VERSION 5.7 ;
  NOWIREEXTENSIONATPIN ON ;
  DIVIDERCHAR "/" ;
  BUSBITCHARS "[]" ;
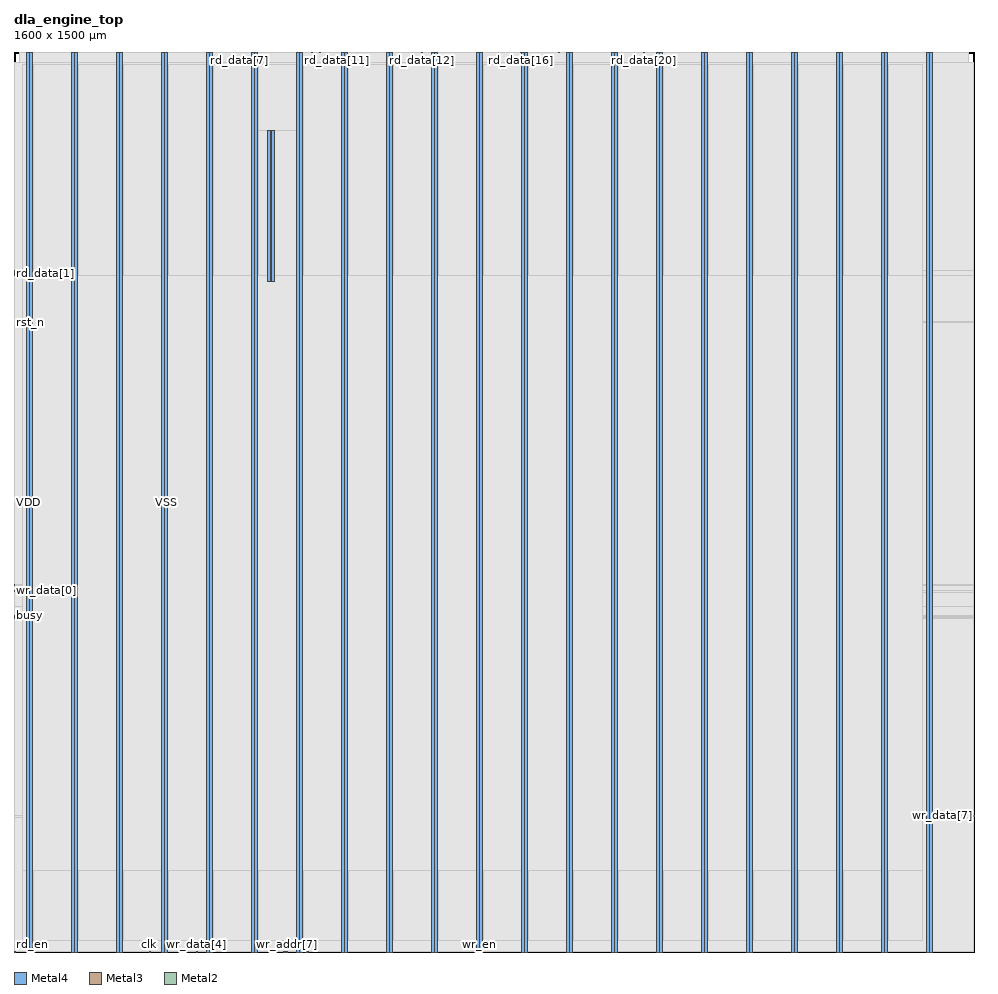
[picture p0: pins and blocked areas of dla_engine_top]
MACRO dla_engine_top
  CLASS BLOCK ;
  FOREIGN dla_engine_top ;
  ORIGIN 0.000 0.000 ;
  SIZE 1600.000 BY 1500.000 ;
  PIN VDD
    DIRECTION INOUT ;
    USE POWER ;
    PORT
      LAYER Metal4 ;
        RECT 20.540 0.000 25.540 1500.000 ;
    END
    PORT
      LAYER Metal4 ;
        RECT 95.540 0.000 100.540 1500.000 ;
    END
    PORT
      LAYER Metal4 ;
        RECT 170.540 0.000 175.540 1500.000 ;
    END
    PORT
      LAYER Metal4 ;
        RECT 245.540 0.000 250.540 1500.000 ;
    END
    PORT
      LAYER Metal4 ;
        RECT 320.540 0.000 325.540 1500.000 ;
    END
    PORT
      LAYER Metal4 ;
        RECT 395.540 0.000 400.540 1500.000 ;
    END
    PORT
      LAYER Metal4 ;
        RECT 470.540 0.000 475.540 1500.000 ;
    END
    PORT
      LAYER Metal4 ;
        RECT 545.540 0.000 550.540 1500.000 ;
    END
    PORT
      LAYER Metal4 ;
        RECT 620.540 0.000 625.540 1500.000 ;
    END
    PORT
      LAYER Metal4 ;
        RECT 695.540 0.000 700.540 1500.000 ;
    END
    PORT
      LAYER Metal4 ;
        RECT 770.540 0.000 775.540 1500.000 ;
    END
    PORT
      LAYER Metal4 ;
        RECT 845.540 0.000 850.540 1500.000 ;
    END
    PORT
      LAYER Metal4 ;
        RECT 920.540 0.000 925.540 1500.000 ;
    END
    PORT
      LAYER Metal4 ;
        RECT 995.540 0.000 1000.540 1500.000 ;
    END
    PORT
      LAYER Metal4 ;
        RECT 1070.540 0.000 1075.540 1500.000 ;
    END
    PORT
      LAYER Metal4 ;
        RECT 1145.540 0.000 1150.540 1500.000 ;
    END
    PORT
      LAYER Metal4 ;
        RECT 1220.540 0.000 1225.540 1500.000 ;
    END
    PORT
      LAYER Metal4 ;
        RECT 1295.540 0.000 1300.540 1500.000 ;
    END
    PORT
      LAYER Metal4 ;
        RECT 1370.540 0.000 1375.540 1500.000 ;
    END
    PORT
      LAYER Metal4 ;
        RECT 1445.540 0.000 1450.540 1500.000 ;
    END
    PORT
      LAYER Metal4 ;
        RECT 1520.540 0.000 1525.540 1500.000 ;
    END
    PORT
      LAYER Metal4 ;
    END
    PORT
      LAYER Metal4 ;
    END
    PORT
      LAYER Metal4 ;
        RECT 422.820 1116.900 427.820 1368.380 ;
    END
  END VDD
  PIN VSS
    DIRECTION INOUT ;
    USE GROUND ;
    PORT
      LAYER Metal4 ;
        RECT 26.540 0.000 31.540 1500.000 ;
    END
    PORT
      LAYER Metal4 ;
        RECT 101.540 0.000 106.540 1500.000 ;
    END
    PORT
      LAYER Metal4 ;
        RECT 176.540 0.000 181.540 1500.000 ;
    END
    PORT
      LAYER Metal4 ;
        RECT 251.540 0.000 256.540 1500.000 ;
    END
    PORT
      LAYER Metal4 ;
        RECT 326.540 0.000 331.540 1500.000 ;
    END
    PORT
      LAYER Metal4 ;
        RECT 401.540 0.000 406.540 1500.000 ;
    END
    PORT
      LAYER Metal4 ;
        RECT 476.540 0.000 481.540 1500.000 ;
    END
    PORT
      LAYER Metal4 ;
        RECT 551.540 0.000 556.540 1500.000 ;
    END
    PORT
      LAYER Metal4 ;
        RECT 626.540 0.000 631.540 1500.000 ;
    END
    PORT
      LAYER Metal4 ;
        RECT 701.540 0.000 706.540 1500.000 ;
    END
    PORT
      LAYER Metal4 ;
        RECT 776.540 0.000 781.540 1500.000 ;
    END
    PORT
      LAYER Metal4 ;
        RECT 851.540 0.000 856.540 1500.000 ;
    END
    PORT
      LAYER Metal4 ;
        RECT 926.540 0.000 931.540 1500.000 ;
    END
    PORT
      LAYER Metal4 ;
        RECT 1001.540 0.000 1006.540 1500.000 ;
    END
    PORT
      LAYER Metal4 ;
        RECT 1076.540 0.000 1081.540 1500.000 ;
    END
    PORT
      LAYER Metal4 ;
        RECT 1151.540 0.000 1156.540 1500.000 ;
    END
    PORT
      LAYER Metal4 ;
        RECT 1226.540 0.000 1231.540 1500.000 ;
    END
    PORT
      LAYER Metal4 ;
        RECT 1301.540 0.000 1306.540 1500.000 ;
    END
    PORT
      LAYER Metal4 ;
        RECT 1376.540 0.000 1381.540 1500.000 ;
    END
    PORT
      LAYER Metal4 ;
        RECT 1451.540 0.000 1456.540 1500.000 ;
    END
    PORT
      LAYER Metal4 ;
        RECT 1526.540 0.000 1531.540 1500.000 ;
    END
    PORT
      LAYER Metal4 ;
    END
    PORT
      LAYER Metal4 ;
    END
    PORT
      LAYER Metal4 ;
        RECT 428.980 1116.900 433.980 1368.380 ;
    END
  END VSS
  PIN busy
    DIRECTION OUTPUT ;
    USE SIGNAL ;
    ANTENNADIFFAREA 1.237600 ;
    PORT
      LAYER Metal3 ;
        RECT 0.000 560.000 0.560 560.560 ;
    END
  END busy
  PIN clk
    DIRECTION INPUT ;
    USE SIGNAL ;
    ANTENNAGATEAREA 4.704000 ;
    ANTENNADIFFAREA 0.877000 ;
    PORT
      LAYER Metal2 ;
        RECT 225.120 0.000 225.680 0.560 ;
    END
  END clk
  PIN done
    DIRECTION OUTPUT ;
    USE SIGNAL ;
    ANTENNADIFFAREA 1.237600 ;
    PORT
      LAYER Metal3 ;
        RECT 0.000 575.680 0.560 576.240 ;
    END
  END done
  PIN rd_addr[0]
    DIRECTION INPUT ;
    USE SIGNAL ;
    ANTENNAGATEAREA 0.666400 ;
    ANTENNADIFFAREA 0.438500 ;
    PORT
      LAYER Metal2 ;
        RECT 495.040 1499.440 495.600 1500.000 ;
    END
  END rd_addr[0]
  PIN rd_addr[1]
    DIRECTION INPUT ;
    USE SIGNAL ;
    ANTENNAGATEAREA 0.666400 ;
    ANTENNADIFFAREA 0.438500 ;
    PORT
      LAYER Metal2 ;
        RECT 498.400 1499.440 498.960 1500.000 ;
    END
  END rd_addr[1]
  PIN rd_addr[2]
    DIRECTION INPUT ;
    USE SIGNAL ;
    ANTENNAGATEAREA 0.666400 ;
    ANTENNADIFFAREA 0.438500 ;
    PORT
      LAYER Metal2 ;
        RECT 493.920 1499.440 494.480 1500.000 ;
    END
  END rd_addr[2]
  PIN rd_addr[3]
    DIRECTION INPUT ;
    USE SIGNAL ;
    ANTENNAGATEAREA 0.666400 ;
    ANTENNADIFFAREA 0.438500 ;
    PORT
      LAYER Metal2 ;
        RECT 496.160 1499.440 496.720 1500.000 ;
    END
  END rd_addr[3]
  PIN rd_data[0]
    DIRECTION OUTPUT ;
    USE SIGNAL ;
    ANTENNADIFFAREA 1.237600 ;
    PORT
      LAYER Metal3 ;
        RECT 0.000 1127.840 0.560 1128.400 ;
    END
  END rd_data[0]
  PIN rd_data[10]
    DIRECTION OUTPUT ;
    USE SIGNAL ;
    ANTENNADIFFAREA 1.237600 ;
    PORT
      LAYER Metal2 ;
        RECT 509.600 1499.440 510.160 1500.000 ;
    END
  END rd_data[10]
  PIN rd_data[11]
    DIRECTION OUTPUT ;
    USE SIGNAL ;
    ANTENNADIFFAREA 1.237600 ;
    PORT
      LAYER Metal2 ;
        RECT 537.600 1499.440 538.160 1500.000 ;
    END
  END rd_data[11]
  PIN rd_data[12]
    DIRECTION OUTPUT ;
    USE SIGNAL ;
    ANTENNADIFFAREA 1.237600 ;
    PORT
      LAYER Metal2 ;
        RECT 679.840 1499.440 680.400 1500.000 ;
    END
  END rd_data[12]
  PIN rd_data[13]
    DIRECTION OUTPUT ;
    USE SIGNAL ;
    ANTENNADIFFAREA 1.237600 ;
    PORT
      LAYER Metal2 ;
        RECT 706.720 1499.440 707.280 1500.000 ;
    END
  END rd_data[13]
  PIN rd_data[14]
    DIRECTION OUTPUT ;
    USE SIGNAL ;
    ANTENNADIFFAREA 1.237600 ;
    PORT
      LAYER Metal2 ;
        RECT 716.800 1499.440 717.360 1500.000 ;
    END
  END rd_data[14]
  PIN rd_data[15]
    DIRECTION OUTPUT ;
    USE SIGNAL ;
    ANTENNADIFFAREA 1.237600 ;
    PORT
      LAYER Metal2 ;
        RECT 745.920 1499.440 746.480 1500.000 ;
    END
  END rd_data[15]
  PIN rd_data[16]
    DIRECTION OUTPUT ;
    USE SIGNAL ;
    ANTENNADIFFAREA 1.237600 ;
    PORT
      LAYER Metal2 ;
        RECT 844.480 1499.440 845.040 1500.000 ;
    END
  END rd_data[16]
  PIN rd_data[17]
    DIRECTION OUTPUT ;
    USE SIGNAL ;
    ANTENNADIFFAREA 1.237600 ;
    PORT
      LAYER Metal2 ;
        RECT 870.240 1499.440 870.800 1500.000 ;
    END
  END rd_data[17]
  PIN rd_data[18]
    DIRECTION OUTPUT ;
    USE SIGNAL ;
    ANTENNADIFFAREA 1.237600 ;
    PORT
      LAYER Metal2 ;
        RECT 879.200 1499.440 879.760 1500.000 ;
    END
  END rd_data[18]
  PIN rd_data[19]
    DIRECTION OUTPUT ;
    USE SIGNAL ;
    ANTENNADIFFAREA 1.237600 ;
    PORT
      LAYER Metal2 ;
        RECT 908.320 1499.440 908.880 1500.000 ;
    END
  END rd_data[19]
  PIN rd_data[1]
    DIRECTION OUTPUT ;
    USE SIGNAL ;
    ANTENNADIFFAREA 1.237600 ;
    PORT
      LAYER Metal3 ;
        RECT 0.000 1131.200 0.560 1131.760 ;
    END
  END rd_data[1]
  PIN rd_data[20]
    DIRECTION OUTPUT ;
    USE SIGNAL ;
    ANTENNADIFFAREA 1.237600 ;
    PORT
      LAYER Metal2 ;
        RECT 1049.440 1499.440 1050.000 1500.000 ;
    END
  END rd_data[20]
  PIN rd_data[21]
    DIRECTION OUTPUT ;
    USE SIGNAL ;
    ANTENNADIFFAREA 1.237600 ;
    PORT
      LAYER Metal2 ;
        RECT 1077.440 1499.440 1078.000 1500.000 ;
    END
  END rd_data[21]
  PIN rd_data[22]
    DIRECTION OUTPUT ;
    USE SIGNAL ;
    ANTENNADIFFAREA 1.237600 ;
    PORT
      LAYER Metal2 ;
        RECT 1087.520 1499.440 1088.080 1500.000 ;
    END
  END rd_data[22]
  PIN rd_data[23]
    DIRECTION OUTPUT ;
    USE SIGNAL ;
    ANTENNADIFFAREA 1.237600 ;
    PORT
      LAYER Metal2 ;
        RECT 1115.520 1499.440 1116.080 1500.000 ;
    END
  END rd_data[23]
  PIN rd_data[2]
    DIRECTION OUTPUT ;
    USE SIGNAL ;
    ANTENNADIFFAREA 1.237600 ;
    PORT
      LAYER Metal3 ;
        RECT 0.000 1132.320 0.560 1132.880 ;
    END
  END rd_data[2]
  PIN rd_data[3]
    DIRECTION OUTPUT ;
    USE SIGNAL ;
    ANTENNADIFFAREA 1.237600 ;
    PORT
      LAYER Metal3 ;
        RECT 0.000 1133.440 0.560 1134.000 ;
    END
  END rd_data[3]
  PIN rd_data[4]
    DIRECTION OUTPUT ;
    USE SIGNAL ;
    ANTENNADIFFAREA 1.237600 ;
    PORT
      LAYER Metal3 ;
        RECT 0.000 1128.960 0.560 1129.520 ;
    END
  END rd_data[4]
  PIN rd_data[5]
    DIRECTION OUTPUT ;
    USE SIGNAL ;
    ANTENNADIFFAREA 1.237600 ;
    PORT
      LAYER Metal3 ;
        RECT 0.000 1130.080 0.560 1130.640 ;
    END
  END rd_data[5]
  PIN rd_data[6]
    DIRECTION OUTPUT ;
    USE SIGNAL ;
    ANTENNADIFFAREA 1.237600 ;
    PORT
      LAYER Metal3 ;
        RECT 0.000 1134.560 0.560 1135.120 ;
    END
  END rd_data[6]
  PIN rd_data[7]
    DIRECTION OUTPUT ;
    USE SIGNAL ;
    ANTENNADIFFAREA 1.237600 ;
    PORT
      LAYER Metal2 ;
        RECT 375.200 1499.440 375.760 1500.000 ;
    END
  END rd_data[7]
  PIN rd_data[8]
    DIRECTION OUTPUT ;
    USE SIGNAL ;
    ANTENNADIFFAREA 1.237600 ;
    PORT
      LAYER Metal2 ;
        RECT 473.760 1499.440 474.320 1500.000 ;
    END
  END rd_data[8]
  PIN rd_data[9]
    DIRECTION OUTPUT ;
    USE SIGNAL ;
    ANTENNADIFFAREA 1.237600 ;
    PORT
      LAYER Metal2 ;
        RECT 500.640 1499.440 501.200 1500.000 ;
    END
  END rd_data[9]
  PIN rd_en
    DIRECTION INPUT ;
    USE SIGNAL ;
    PORT
      LAYER Metal2 ;
        RECT 1.120 0.000 1.680 0.560 ;
    END
  END rd_en
  PIN rst_n
    DIRECTION INPUT ;
    USE SIGNAL ;
    ANTENNAGATEAREA 0.666400 ;
    ANTENNADIFFAREA 0.438500 ;
    PORT
      LAYER Metal3 ;
        RECT 0.000 1049.440 0.560 1050.000 ;
    END
  END rst_n
  PIN start
    DIRECTION INPUT ;
    USE SIGNAL ;
    ANTENNAGATEAREA 0.666400 ;
    ANTENNADIFFAREA 0.438500 ;
    PORT
      LAYER Metal3 ;
        RECT 0.000 556.640 0.560 557.200 ;
    END
  END start
  PIN wb_done
    DIRECTION OUTPUT ;
    USE SIGNAL ;
    ANTENNADIFFAREA 1.237600 ;
    PORT
      LAYER Metal3 ;
        RECT 0.000 611.520 0.560 612.080 ;
    END
  END wb_done
  PIN wr_addr[0]
    DIRECTION INPUT ;
    USE SIGNAL ;
    ANTENNAGATEAREA 0.666400 ;
    ANTENNADIFFAREA 0.438500 ;
    PORT
      LAYER Metal2 ;
        RECT 486.080 0.000 486.640 0.560 ;
    END
  END wr_addr[0]
  PIN wr_addr[1]
    DIRECTION INPUT ;
    USE SIGNAL ;
    ANTENNAGATEAREA 0.666400 ;
    ANTENNADIFFAREA 0.438500 ;
    PORT
      LAYER Metal2 ;
        RECT 480.480 0.000 481.040 0.560 ;
    END
  END wr_addr[1]
  PIN wr_addr[2]
    DIRECTION INPUT ;
    USE SIGNAL ;
    ANTENNAGATEAREA 0.666400 ;
    ANTENNADIFFAREA 0.438500 ;
    PORT
      LAYER Metal2 ;
        RECT 449.120 0.000 449.680 0.560 ;
    END
  END wr_addr[2]
  PIN wr_addr[3]
    DIRECTION INPUT ;
    USE SIGNAL ;
    ANTENNAGATEAREA 0.666400 ;
    ANTENNADIFFAREA 0.438500 ;
    PORT
      LAYER Metal2 ;
        RECT 450.240 0.000 450.800 0.560 ;
    END
  END wr_addr[3]
  PIN wr_addr[4]
    DIRECTION INPUT ;
    USE SIGNAL ;
    ANTENNAGATEAREA 0.666400 ;
    ANTENNADIFFAREA 0.438500 ;
    PORT
      LAYER Metal2 ;
        RECT 451.360 0.000 451.920 0.560 ;
    END
  END wr_addr[4]
  PIN wr_addr[5]
    DIRECTION INPUT ;
    USE SIGNAL ;
    ANTENNAGATEAREA 0.666400 ;
    ANTENNADIFFAREA 0.438500 ;
    PORT
      LAYER Metal2 ;
        RECT 452.480 0.000 453.040 0.560 ;
    END
  END wr_addr[5]
  PIN wr_addr[6]
    DIRECTION INPUT ;
    USE SIGNAL ;
    ANTENNAGATEAREA 0.666400 ;
    ANTENNADIFFAREA 0.438500 ;
    PORT
      LAYER Metal2 ;
        RECT 453.600 0.000 454.160 0.560 ;
    END
  END wr_addr[6]
  PIN wr_addr[7]
    DIRECTION INPUT ;
    USE SIGNAL ;
    ANTENNAGATEAREA 0.666400 ;
    ANTENNADIFFAREA 0.438500 ;
    PORT
      LAYER Metal2 ;
        RECT 454.720 0.000 455.280 0.560 ;
    END
  END wr_addr[7]
  PIN wr_addr[8]
    DIRECTION INPUT ;
    USE SIGNAL ;
    ANTENNAGATEAREA 0.666400 ;
    ANTENNADIFFAREA 0.438500 ;
    PORT
      LAYER Metal2 ;
        RECT 489.440 0.000 490.000 0.560 ;
    END
  END wr_addr[8]
  PIN wr_addr[9]
    DIRECTION INPUT ;
    USE SIGNAL ;
    ANTENNAGATEAREA 0.666400 ;
    ANTENNADIFFAREA 0.438500 ;
    PORT
      LAYER Metal2 ;
        RECT 488.320 0.000 488.880 0.560 ;
    END
  END wr_addr[9]
  PIN wr_data[0]
    DIRECTION INPUT ;
    USE SIGNAL ;
    ANTENNAGATEAREA 0.666400 ;
    ANTENNADIFFAREA 0.438500 ;
    PORT
      LAYER Metal3 ;
        RECT 0.000 601.440 0.560 602.000 ;
    END
  END wr_data[0]
  PIN wr_data[1]
    DIRECTION INPUT ;
    USE SIGNAL ;
    ANTENNAGATEAREA 0.666400 ;
    ANTENNADIFFAREA 0.438500 ;
    PORT
      LAYER Metal3 ;
        RECT 0.000 600.320 0.560 600.880 ;
    END
  END wr_data[1]
  PIN wr_data[2]
    DIRECTION INPUT ;
    USE SIGNAL ;
    ANTENNAGATEAREA 0.666400 ;
    ANTENNADIFFAREA 0.438500 ;
    PORT
      LAYER Metal3 ;
        RECT 0.000 599.200 0.560 599.760 ;
    END
  END wr_data[2]
  PIN wr_data[3]
    DIRECTION INPUT ;
    USE SIGNAL ;
    ANTENNAGATEAREA 0.666400 ;
    ANTENNADIFFAREA 0.438500 ;
    PORT
      LAYER Metal2 ;
        RECT 226.240 0.000 226.800 0.560 ;
    END
  END wr_data[3]
  PIN wr_data[4]
    DIRECTION INPUT ;
    USE SIGNAL ;
    ANTENNAGATEAREA 0.666400 ;
    ANTENNADIFFAREA 0.438500 ;
    PORT
      LAYER Metal2 ;
        RECT 304.640 0.000 305.200 0.560 ;
    END
  END wr_data[4]
  PIN wr_data[5]
    DIRECTION INPUT ;
    USE SIGNAL ;
    ANTENNAGATEAREA 0.666400 ;
    ANTENNADIFFAREA 0.438500 ;
    PORT
      LAYER Metal3 ;
        RECT 1599.440 225.120 1600.000 225.680 ;
    END
  END wr_data[5]
  PIN wr_data[6]
    DIRECTION INPUT ;
    USE SIGNAL ;
    ANTENNAGATEAREA 0.666400 ;
    ANTENNADIFFAREA 0.438500 ;
    PORT
      LAYER Metal3 ;
        RECT 1599.440 226.240 1600.000 226.800 ;
    END
  END wr_data[6]
  PIN wr_data[7]
    DIRECTION INPUT ;
    USE SIGNAL ;
    ANTENNAGATEAREA 0.666400 ;
    ANTENNADIFFAREA 0.438500 ;
    PORT
      LAYER Metal3 ;
        RECT 1599.440 227.360 1600.000 227.920 ;
    END
  END wr_data[7]
  PIN wr_en
    DIRECTION INPUT ;
    USE SIGNAL ;
    ANTENNAGATEAREA 0.666400 ;
    ANTENNADIFFAREA 0.438500 ;
    PORT
      LAYER Metal2 ;
        RECT 776.160 0.000 776.720 0.560 ;
    END
  END wr_en
  PIN wr_sel
    DIRECTION INPUT ;
    USE SIGNAL ;
    ANTENNAGATEAREA 0.666400 ;
    ANTENNADIFFAREA 0.438500 ;
    PORT
      LAYER Metal2 ;
        RECT 778.400 0.000 778.960 0.560 ;
    END
  END wr_sel
  OBS
      LAYER Nwell ;
        RECT 6.290 15.250 1593.630 1482.190 ;
      LAYER Metal1 ;
        RECT 6.720 15.380 1593.200 1482.060 ;
      LAYER Metal2 ;
        RECT 8.820 1499.140 374.900 1499.860 ;
        RECT 376.060 1499.140 473.460 1499.860 ;
        RECT 474.620 1499.140 493.620 1499.860 ;
        RECT 497.020 1499.140 498.100 1499.860 ;
        RECT 499.260 1499.140 500.340 1499.860 ;
        RECT 501.500 1499.140 509.300 1499.860 ;
        RECT 510.460 1499.140 537.300 1499.860 ;
        RECT 538.460 1499.140 679.540 1499.860 ;
        RECT 680.700 1499.140 706.420 1499.860 ;
        RECT 707.580 1499.140 716.500 1499.860 ;
        RECT 717.660 1499.140 745.620 1499.860 ;
        RECT 746.780 1499.140 844.180 1499.860 ;
        RECT 845.340 1499.140 869.940 1499.860 ;
        RECT 871.100 1499.140 878.900 1499.860 ;
        RECT 880.060 1499.140 908.020 1499.860 ;
        RECT 909.180 1499.140 1049.140 1499.860 ;
        RECT 1050.300 1499.140 1077.140 1499.860 ;
        RECT 1078.300 1499.140 1087.220 1499.860 ;
        RECT 1088.380 1499.140 1115.220 1499.860 ;
        RECT 1116.380 1499.140 1591.100 1499.860 ;
        RECT 8.820 0.860 1591.100 1499.140 ;
        RECT 8.820 0.090 224.820 0.860 ;
        RECT 227.100 0.090 304.340 0.860 ;
        RECT 305.500 0.090 448.820 0.860 ;
        RECT 455.580 0.090 480.180 0.860 ;
        RECT 481.340 0.090 485.780 0.860 ;
        RECT 486.940 0.090 488.020 0.860 ;
        RECT 490.300 0.090 775.860 0.860 ;
        RECT 777.020 0.090 778.100 0.860 ;
        RECT 779.260 0.090 1591.100 0.860 ;
      LAYER Metal3 ;
        RECT 0.560 1135.420 1599.440 1482.740 ;
        RECT 0.860 1127.540 1599.440 1135.420 ;
        RECT 0.560 1050.300 1599.440 1127.540 ;
        RECT 0.860 1049.140 1599.440 1050.300 ;
        RECT 0.560 612.380 1599.440 1049.140 ;
        RECT 0.860 611.220 1599.440 612.380 ;
        RECT 0.560 602.300 1599.440 611.220 ;
        RECT 0.860 598.900 1599.440 602.300 ;
        RECT 0.560 576.540 1599.440 598.900 ;
        RECT 0.860 575.380 1599.440 576.540 ;
        RECT 0.560 560.860 1599.440 575.380 ;
        RECT 0.860 559.700 1599.440 560.860 ;
        RECT 0.560 557.500 1599.440 559.700 ;
        RECT 0.860 556.340 1599.440 557.500 ;
        RECT 0.560 228.220 1599.440 556.340 ;
        RECT 0.560 224.820 1599.140 228.220 ;
        RECT 0.560 0.140 1599.440 224.820 ;
      LAYER Metal4 ;
        RECT 422.820 136.900 427.820 388.380 ;
        RECT 422.820 622.980 427.820 882.300 ;
        RECT 428.980 136.900 433.980 388.380 ;
        RECT 428.980 622.980 433.980 882.300 ;
        RECT 13.580 18.570 20.240 1479.430 ;
        RECT 25.840 18.570 26.240 1479.430 ;
        RECT 31.840 18.570 95.240 1479.430 ;
        RECT 100.840 18.570 101.240 1479.430 ;
        RECT 106.840 18.570 170.240 1479.430 ;
        RECT 175.840 18.570 176.240 1479.430 ;
        RECT 181.840 18.570 245.240 1479.430 ;
        RECT 250.840 18.570 251.240 1479.430 ;
        RECT 256.840 18.570 320.240 1479.430 ;
        RECT 325.840 18.570 326.240 1479.430 ;
        RECT 331.840 18.570 395.240 1479.430 ;
        RECT 400.840 18.570 401.240 1479.430 ;
        RECT 406.840 1368.680 470.240 1479.430 ;
        RECT 406.840 1116.600 422.520 1368.680 ;
        RECT 428.120 1116.600 428.680 1368.680 ;
        RECT 434.280 1116.600 470.240 1368.680 ;
        RECT 406.840 882.600 470.240 1116.600 ;
        RECT 406.840 622.680 422.520 882.600 ;
        RECT 428.120 622.680 428.680 882.600 ;
        RECT 434.280 622.680 470.240 882.600 ;
        RECT 406.840 388.680 470.240 622.680 ;
        RECT 406.840 136.600 422.520 388.680 ;
        RECT 428.120 136.600 428.680 388.680 ;
        RECT 434.280 136.600 470.240 388.680 ;
        RECT 406.840 18.570 470.240 136.600 ;
        RECT 475.840 18.570 476.240 1479.430 ;
        RECT 481.840 18.570 545.240 1479.430 ;
        RECT 550.840 18.570 551.240 1479.430 ;
        RECT 556.840 18.570 620.240 1479.430 ;
        RECT 625.840 18.570 626.240 1479.430 ;
        RECT 631.840 18.570 695.240 1479.430 ;
        RECT 700.840 18.570 701.240 1479.430 ;
        RECT 706.840 18.570 770.240 1479.430 ;
        RECT 775.840 18.570 776.240 1479.430 ;
        RECT 781.840 18.570 845.240 1479.430 ;
        RECT 850.840 18.570 851.240 1479.430 ;
        RECT 856.840 18.570 920.240 1479.430 ;
        RECT 925.840 18.570 926.240 1479.430 ;
        RECT 931.840 18.570 995.240 1479.430 ;
        RECT 1000.840 18.570 1001.240 1479.430 ;
        RECT 1006.840 18.570 1070.240 1479.430 ;
        RECT 1075.840 18.570 1076.240 1479.430 ;
        RECT 1081.840 18.570 1145.240 1479.430 ;
        RECT 1150.840 18.570 1151.240 1479.430 ;
        RECT 1156.840 18.570 1220.240 1479.430 ;
        RECT 1225.840 18.570 1226.240 1479.430 ;
        RECT 1231.840 18.570 1295.240 1479.430 ;
        RECT 1300.840 18.570 1301.240 1479.430 ;
        RECT 1306.840 18.570 1370.240 1479.430 ;
        RECT 1375.840 18.570 1376.240 1479.430 ;
        RECT 1381.840 18.570 1445.240 1479.430 ;
        RECT 1450.840 18.570 1451.240 1479.430 ;
        RECT 1456.840 18.570 1514.100 1479.430 ;
      LAYER Metal5 ;
        RECT 13.500 135.230 1514.180 1127.470 ;
  END
END dla_engine_top
END LIBRARY

